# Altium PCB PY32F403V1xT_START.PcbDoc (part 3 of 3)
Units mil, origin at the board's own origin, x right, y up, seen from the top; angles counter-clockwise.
Board outline 1968.43 x 4717 mil, 2 copper layers (Top Layer, Bottom Layer), stack 21 mil thick; 170 components, 200 nets, 718 pads, 400 vias.
Unrouted connection lines stored in the file: 1.

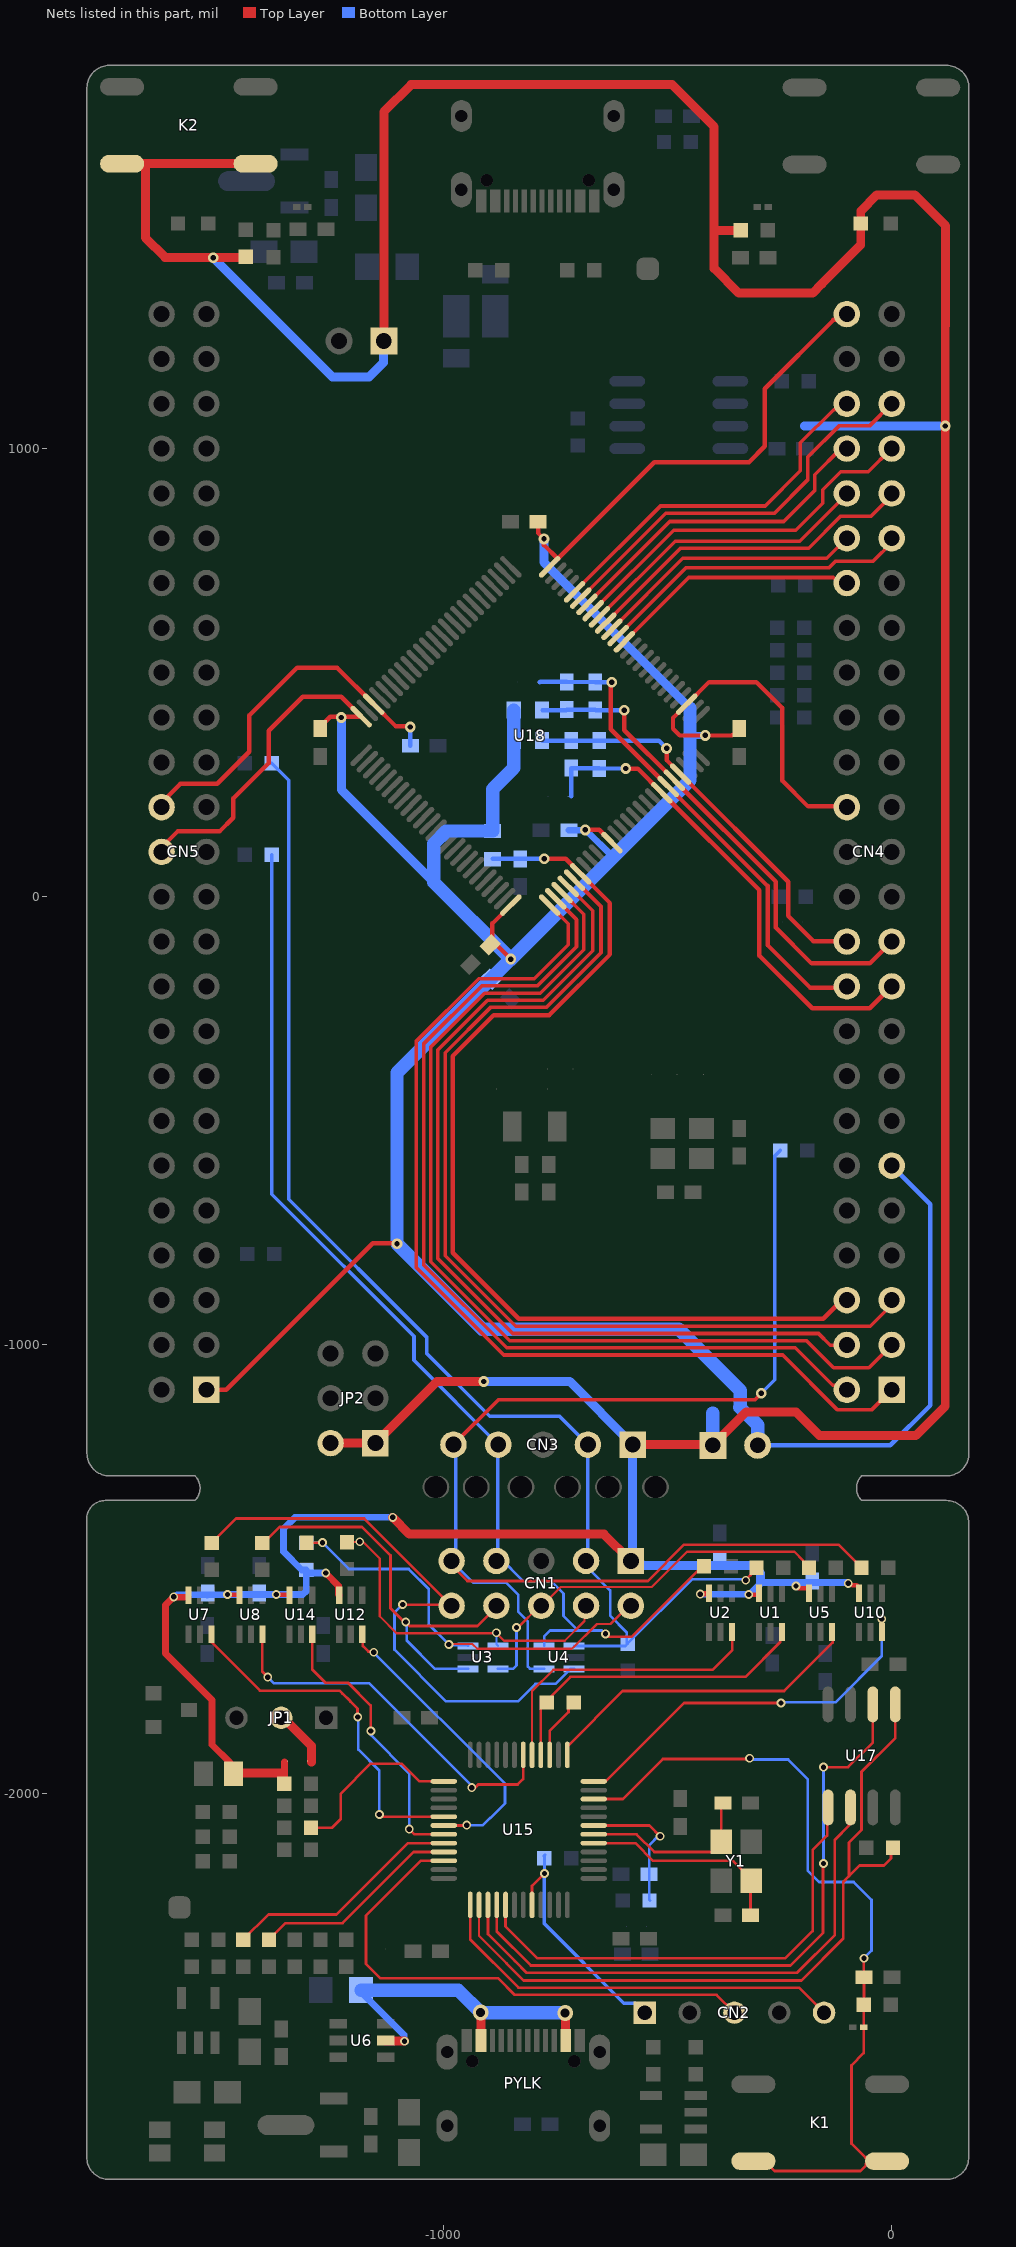
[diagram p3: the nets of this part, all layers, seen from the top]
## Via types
v1: diameter 24, hole 12, Top Layer to Bottom Layer, tented both sides, 237 vias
v2: diameter 19.68, hole 11.81, Top Layer to Bottom Layer, tented both sides, 106 vias
v3: diameter 19.68, hole 11.81, Top Layer to Bottom Layer, 38 vias
v4: diameter 35, hole 20, Top Layer to Bottom Layer, tented both sides, 11 vias
v5: diameter 40, hole 20, Top Layer to Bottom Layer, tented both sides, 6 vias
v6: diameter 30, hole 15, Top Layer to Bottom Layer, tented both sides, 2 vias

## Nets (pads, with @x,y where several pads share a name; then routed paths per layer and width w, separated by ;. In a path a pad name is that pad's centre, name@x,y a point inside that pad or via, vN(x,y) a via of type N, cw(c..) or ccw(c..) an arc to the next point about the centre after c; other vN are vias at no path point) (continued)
PE2: CN4.1 U18.1 | length 2250.2
  Top Layer w8: U18.1@-763.37,-18.46 -721.75,-60.08 -721.75,-107.37 -797.33,-182.95 -921.6,-182.95 -1060.44,-321.79 -1060.44,-827.94 -865.89,-1022.49 -243.25,-1022.49 -120.73,-1145 -45,-1145 CN4.1@0,-1100
PE3: CN4.2 U18.2 | length 2109.7
  Top Layer w8: U18.2@-749.46,-4.54 -703.17,-50.83 -703.17,-111.42 -790.7,-198.95 -914.97,-198.95 -1044.44,-328.41 -1044.44,-820.92 -858.87,-1006.49 -215.22,-1006.49 -131.47,-1090.23 -109.77,-1090.23 CN4.2@-100,-1100
PE4: CN4.3 U18.3 | length 2205.2
  Top Layer w8: U18.3@-735.54,9.38 -687.17,-38.98 -687.17,-118.04 -784.08,-214.95 -908.35,-214.95 -1028.44,-335.04 -1028.44,-814.29 -852.24,-990.49 -189.92,-990.49 -129.68,-1050.73 -50.73,-1050.73 CN4.3@0,-1000
PE5: CN4.4 U18.4 | length 2067.1
  Top Layer w8: U18.4@-721.62,23.3 -667.26,-31.07 -667.26,-120.76 -777.45,-230.95 -901.72,-230.95 -1012.44,-341.67 -1012.44,-807.66 -845.61,-974.49 -163.21,-974.49 -136.84,-1000.85 -112.98,-1000.85 -106.92,-1006.92 CN4.4@-100,-1000
PE6: CN4.5 U18.5 | length 2171.5
  Top Layer w8: U18.5@-707.7,37.22 -648.68,-21.8 -648.68,-124.81 -770.82,-246.95 -895.09,-246.95 -996.44,-348.3 -996.44,-801.03 -838.99,-958.49 -181.02,-958.49 ; -181,-958.47 -48.15,-958.47 0,-910.32 CN4.5@0,-900
PE7: CN4.38 U18.38 | length 560.9
  Top Layer w8: U18.38@-596.34,568.94 -452.84,712.44 -130.21,712.44 -127.55,709.77 -109.77,709.77 CN4.38@-100,700
PE8: CN4.39 U18.39 | length 706
  Top Layer w8: U18.39@-610.27,582.86 -459.39,733.73 -140.26,733.73 -124.98,749.02 -41.05,749.02 0,790.07 CN4.39@0,800
PE9: CN4.40 U18.40 | length 608.4
  Top Layer w8: U18.40@-624.18,596.78 -465.84,755.12 -144.88,755.12 CN4.40@-100,800
PE10: CN4.41 U18.41 | length 760.7
  Top Layer w8: U18.41@-638.1,610.7 -471.4,777.4 -185.4,777.4 -113.36,849.44 -45.76,849.44 0,895.2 CN4.41@0,900
PE11: CN4.42 U18.42 | length 667.1
  Top Layer w8: U18.42@-652.02,624.62 -483.23,793.4 -204.85,793.4 -100,898.25 CN4.42@-100,900
PE12: CN4.43 U18.43 | length 833.4
  Top Layer w8: U18.43@-665.94,638.54 -486.6,817.88 -214.28,817.88 -154.17,878 -154.17,908.32 -113.99,948.5 -52.05,948.5 -0.55,1000 CN4.43@0,1000
PE13: CN4.44 U18.44 | length 744.3
  Top Layer w8: U18.44@-679.86,652.45 -495.04,837.28 -240.81,837.28 -171.71,906.37 -171.71,941.4 -113.11,1000 CN4.44@-100,1000
PE14: CN4.45 U18.45 | length 902.7
  Top Layer w8: U18.45@-693.78,666.38 -504.2,855.96 -261.48,855.96 -187.71,929.73 -187.71,980.43 -117.59,1050.55 -49.49,1050.55 CN4.45@-0.3,1099.74
PE15: CN4.46 U18.46 | length 817.9
  Top Layer w8: U18.46@-707.7,680.29 -516.03,871.96 -282.46,871.96 -203.71,950.71 -203.71,1012.82 -129.63,1086.9 -126.92,1086.9 -113.82,1100 CN4.46@-100,1100
PYLK_BOOT0: CN2.1 R28.1 U15.44 | length 531.3
  Top Layer w6: U15.44@-802.47,-2249.32 -802.47,-2206.93 v2(-774.79,-2179.25)
  Bottom Layer w6: v2(-774.79,-2179.25) -774.79,-2142.1 -776.51,-2140.37 R28.1@-773.74,-2137.6
  Bottom Layer w8: v2(-774.79,-2179.25) -774.79,-2291.51 -597.6,-2468.7 -571.9,-2468.7 -564,-2476.6 CN2.1@-564,-2483.1
PYLK_KEY: C6.2 K1.1 K1.2 R16.1 U11.1 U15.10 | length 1855
  Top Layer w6: U15.10@-664.68,-2013.1 -599.86,-2013.1 -510.56,-1923.8 -318.8,-1923.8 v2(-317,-1922) ; K1.2@-320.45,-2813 -291.75,-2813 -261.5,-2843.25 -69.64,-2843.25 -57.98,-2831.59 -57.98,-2827.49 K1.1@-43.49,-2813 ; v2(-62,-2368.3) -62,-2410.6 C6.2@-61.8,-2410.8 -61.8,-2471.8 R16.1@-62,-2472 -62.4,-2472.4 U11.1@-62.4,-2522.3 -62.4,-2580 -89.7,-2607.3 -89.7,-2782 -58.7,-2813 K1.1@-43.49,-2813 ; K1.1@-22.45,-2813 K1.1@-43.49,-2813
  Bottom Layer w6: v2(-317,-1922) -313.94,-1925.06 -304.38,-1925.06 -304.31,-1925.12 -231.08,-1925.12 -187,-1969.2 -187,-2173.24 -162.1,-2198.14 -84.96,-2198.14 -45,-2238.1 -45,-2351.3 v2(-62,-2368.3)
PYLK_NRST: C24.2 R36.1 U15.7 | length 314.8
  Top Layer w6: U15.7@-664.68,-2072.16 -540.64,-2072.16 v2(-516.6,-2096.2)
  Bottom Layer w6: R36.1@-539.3,-2239.6 -540.88,-2238.02 -540.88,-2181.2 -540.88,-2116 -521.08,-2096.2 v2(-516.6,-2096.2)
PYLK_OSCIN: C19.2 U15.5 Y1.3 | length 465.6
  Top Layer w6: U15.5@-664.68,-2111.53 -571.95,-2111.53 -532.58,-2150.9 -353.89,-2150.9 -313.41,-2191.37 Y1.3@-313.41,-2195.31 -314.88,-2196.78 C19.2@-314.88,-2272
PYLK_OSCOUT: C25.2 U15.6 Y1.1 | length 399.8
  Top Layer w6: U15.6@-664.68,-2091.84 -569.01,-2091.84 -529.64,-2131.21 -399.97,-2131.21 -380.34,-2111.59 Y1.1@-380.34,-2108.69 -380.34,-2025.46 C25.2@-376.88,-2022
PYLK_SPI_CS: R35.1 U15.38 U17.1 | length 1667.6
  Top Layer w5: U15.38@-920.58,-2249.32 -920.58,-2318.38 -859.34,-2379.62
  Top Layer w6: -859.34,-2379.62 -821.05,-2417.91 -201.49,-2417.91 -108.12,-2324.53 -108.12,-2198.12 -95.23,-2185.23 ; R35.1@3,-2122 -1.38,-2126.38 -1.38,-2145.31 -17.64,-2161.58 -71.58,-2161.58 -95.23,-2185.23 ; U17.1@8,-1802 8,-1877 -67.31,-1952.31 -67.31,-2081.99 -95.23,-2109.91 -95.23,-2185.23
PYLK_SPI_MISO: U15.40 U17.2 | length 1437.2
  Top Layer w6: U15.40@-881.21,-2249.32 -881.21,-2308.7 -805.2,-2384.7 -226,-2384.7 -153.1,-2311.8 -153.1,-2158.1 v2(-152,-2157) ; v2(-152,-1942) -97,-1942 -42,-1887 U17.2@-42,-1802
  Bottom Layer w6: v2(-152,-2157) v2(-152,-1942)
PYLK_SPI_MOSI: U15.41 U17.5 | length 1077.9
  Top Layer w6: U15.41@-861.53,-2249.32 -861.53,-2297.51 -790.34,-2368.7 -237.58,-2368.7 -176.47,-2307.59 -176.47,-2126.91 -143.87,-2094.31 -143.87,-2033.87 U17.5@-142,-2032
PYLK_SPI_SCK: U15.39 U17.6 | length 1208.9
  Top Layer w6: U15.39@-900.9,-2249.32 -900.9,-2314.64 -840.68,-2374.86 -814.83,-2400.7 -210.93,-2400.7 -126.79,-2316.56 -126.79,-2103.94 -95.06,-2072.21 -95.06,-2035.06 U17.6@-92,-2032
SWD_SCK: CN2.5 U15.37 | length 934
  Top Layer w6: U15.37@-940.27,-2249.32 -940.27,-2326.25 -832.52,-2434 -330,-2434 -206.6,-2434 CN2.5@-150.9,-2489.7
SWD_SDA: CN2.3 U15.34 | length 1199.5
  Top Layer w6: U15.34@-999.32,-2150.9 -1050.89,-2150.9 -1172.95,-2272.96 -1172.95,-2381.29 -1141.43,-2412.8 -878.25,-2412.8 -841.05,-2450 -514,-2450 -390.6,-2450 CN2.3@-350.9,-2489.7
T_RESET: CN1.9 CN3.5 R18.2 R40.1 U4.4 | length 2919.2
  Top Layer w6: CN1.9@-974.22,-1499.22 -946.8,-1526.64 -544.09,-1526.64 -463.01,-1445.56 -118.94,-1445.56 R18.2@-67.51,-1497
  Top Layer w8: CN3.5@-977.74,-1222.44 -976.49,-1221.18 -877.3,-1122 -305,-1122 v1(-291,-1108)
  Bottom Layer w6: CN1.9@-982,-1482 -933.78,-1530.22 -860.98,-1530.22 -832.9,-1558.31 -832.9,-1595.58 -811.85,-1616.63 -811.85,-1717.69 -807.39,-1722.15 -775.91,-1722.15 U4.4@-775.46,-1722.59
  Bottom Layer w8: CN1.9@-982,-1482 -972.96,-1472.96 -972.96,-1227.22 CN3.5@-977.74,-1222.44 ; v1(-291,-1108) -260.91,-1077.91 -260.91,-582.69 -260.55,-582.33 -260.55,-578 R40.1@-248.55,-566
T_RESETa: U10.3 U15.12 | length 870.1
  Top Layer w6: U15.12@-664.68,-1973.73 -638.21,-1973.73 -463.53,-1799.04 -375.47,-1799.04 v2(-247.09,-1799.04) ; v2(-22.18,-1611.3) -21.92,-1611.56 U10.3@-21.92,-1640.31
  Bottom Layer w6: v2(-247.09,-1799.04) -245.35,-1797.3 -125.6,-1797.3 -22.18,-1693.89 v2(-22.18,-1611.3)
T_RTCK_DTRa: U5.3 U15.13 | length 731.2
  Top Layer w6: U15.13@-723.73,-1914.68 -723.73,-1895.43 -600.3,-1772 -240.01,-1772 -131.82,-1663.81 -131.82,-1641.84 U5.3@-133.34,-1640.31
T_RTCK_VCP_DTR: CN1.6 R10.2 U3.5 | length 868.3
  Top Layer w5: v2(-837.19,-1630.33) -833.76,-1630.33 -785.43,-1582 CN1.6@-782,-1582 -780.37,-1582 -738.51,-1540.14 -535.27,-1540.14 -456.7,-1461.56 -217.02,-1461.56 -196.65,-1481.93 -196.65,-1485 R10.2@-184.65,-1497
  Bottom Layer w6: U3.5@-878.54,-1722.59 -844.49,-1722.59 -837.19,-1715.29 v2(-837.19,-1630.33)
T_TCK_SWCLK: CN1.7 CN3.4 R7.2 R39.1 U4.5 | length 2512.5
  Top Layer w6: CN1.7@-877,-1472 CN1.7@-875.65,-1470.65 ; v2(-638.5,-1644.68) -631.86,-1651.31 -580.04,-1651.31 -425.72,-1497 R7.2@-418.94,-1497
  Bottom Layer w6: CN1.7@-874.5,-1474.5 -821.53,-1527.47 -759.35,-1527.47 -732.4,-1554.43 -732.4,-1604.46 -699.86,-1637 ; U4.5@-775.46,-1671.41 -775.46,-1650.46 -762,-1637 -699.86,-1637 ; v2(-638.5,-1644.68) -646.18,-1637 -699.86,-1637
  Bottom Layer w8: R39.1@-1383.09,94 -1383.09,-663.41 -1065.8,-980.7 -1065.8,-1034.38 CN3.4@-877.74,-1222.44 ; CN1.7@-882,-1482 -879.21,-1479.21 CN3.4@-879.21,-1222.44
T_TCK_SWCLKa: U2.3 U15.17 | length 668.1
  Top Layer w5: U15.17@-802.47,-1914.68 -802.47,-1772.24 -755.23,-1725
  Top Layer w6: -755.23,-1725 -649.38,-1725 -399.57,-1725 -355.59,-1681.02 -355.59,-1640.92 U2.3@-356.2,-1640.31
T_TDI_VCP_TX: CN1.4 R22.2 U3.4 | length 783.1
  Top Layer w5: R22.2@-1215.37,-1439.89 -1179.1,-1439.89 -1142.46,-1476.52 -1142.46,-1605.38 -1104.71,-1643.14 v2@-882,-1643.14 ; R22.2@-1215.37,-1436.89 R22.2@-1213.87,-1438.39 ; v2@-881.98,-1643.14 -865.22,-1659.89 -729.24,-1659.89 -685.44,-1616.1 -685.44,-1585.44 CN1.4@-682,-1582
  Bottom Layer w5: v2@-881.94,-1642.06 -881.94,-1668 U3.4@-878.54,-1671.41
  other v2: -882,-1642
  other v3: -1187.04,-1439.02
T_TDI_VCP_TXa: U12.3 U15.30 | length 672.4
  Top Layer w6: U12.3@-1181.29,-1645.31 -1180.07,-1646.53 -1180.07,-1671.63 -1167.76,-1683.94 -1157.44,-1683.94 v2(-1155.69,-1685.69) ; U15.30@-999.32,-2072.16 -948.98,-2072.16 v2(-948.24,-2071.42)
  Bottom Layer w6: v2(-1155.69,-1685.69) -862.91,-1978.47 -862.91,-2023.08 -895.44,-2055.62 -896.29,-2055.62 -912.09,-2071.42 v2(-948.24,-2071.42)
T_TDO_SWO: CN1.10 R13.2 U4.3 | length 1333.3
  Top Layer w6: R13.2@-1517.34,-1441.92 -1462.53,-1387.1 -1176.9,-1387.1 CN1.10@-988.49,-1575.51 ; v2(-1091.13,-1579.25) -1090.46,-1579.92 -992.9,-1579.92 CN1.10@-988.49,-1575.51 ; CN1.10@-982,-1582 CN1.10@-988.49,-1575.51
  Bottom Layer w6: v2(-1091.13,-1579.25) -1109.17,-1597.28 -1109.17,-1679.92 -993.94,-1795.14 -833.71,-1795.14 -794.58,-1756.01 -750.55,-1756.01 -717.12,-1722.59 U4.3@-708.54,-1722.59 U4.3@-710.85,-1724.9
T_TDO_SWOa: U7.3 U15.29 | length 807.7
  Top Layer w6: U7.3@-1517.86,-1645.31 -1517.86,-1663.14 -1409.54,-1771.46 -1231.92,-1771.46 -1225.37,-1778 -1224.99,-1778 -1208,-1794.99 -1208,-1795.37 -1192.07,-1811.3 -1192.07,-1829.31 v2(-1191.38,-1830) ; v2(-1143.12,-2047.67) -1138.32,-2052.47 -1055.45,-2052.47 U15.29@-999.32,-2052.47
  Bottom Layer w6: v2(-1191.38,-1830) -1190.05,-1831.32 -1190.05,-1903.07 -1143.12,-1950 v2(-1143.12,-2047.67)
T_TMS_SWDIO: CN1.3 CN3.2 R2.2 R5.2 R37.1 U4.1 | length 2854.9
  Top Layer w6: CN1.3@-677.63,-1495.81 CN1.3@-671.44,-1502 ; v2@-325.38,-1523.69 -314.79,-1513.1 -314.79,-1510 R2.2@-301.79,-1497
  Bottom Layer w6: U4.1@-708.23,-1671.71 -594.21,-1671.71 R5.2@-589.1,-1666.6 ; CN1.3@-673.41,-1502.3 -628.14,-1547.58 -628.14,-1604.11 -591.19,-1641.06 -591.19,-1664.51 R5.2@-589.1,-1666.6 ; v2(-325.57,-1524.93) -327.75,-1522.75 -445.25,-1522.75 R5.2@-589.1,-1666.6
  Bottom Layer w8: R37.1@-1383.09,298 -1345,259.91 -1345,-675.04 -1037.8,-982.24 -1037.8,-1018.2 -896.91,-1159.09 -741.09,-1159.09 CN3.2@-677.74,-1222.44 -678,-1222.7 -678,-1478 CN1.3@-682,-1482
T_TMS_SWDIOa: R32.1 U1.3 U15.16 | length 723.8
  Top Layer w6: U15.16@-782.79,-1914.68 R32.1@-782.79,-1794.63 ; R32.1@-769.54,-1797.63 -769.54,-1793.01 -716.88,-1740.35 -660.3,-1740.35 -325.78,-1740.35 -248.66,-1663.23 -248.66,-1644.2 U1.3@-244.77,-1640.31
T_TMS_SWDIOa_OUT: R32.2 U15.15 | length 143.2
  Top Layer w6: U15.15@-763.1,-1914.68 -763.1,-1861.36 -721.18,-1819.44 R32.2@-721.18,-1788.84
T_TRST_RTSa: U8.3 U15.18 | length 840.3
  Top Layer w6: U8.3@-1404.14,-1645.31 -1404.14,-1729.14 v2(-1392.18,-1741.1) ; v2(-937.08,-1987.65) -933.17,-1991.56 -922.46,-1980.84 -834.61,-1980.84 -822.16,-1968.4 U15.18@-822.16,-1914.68
  Bottom Layer w6: v2(-1392.18,-1741.1) -1378.19,-1755.09 -1165.35,-1755.09 -937.08,-1983.36 v2(-937.08,-1987.65)
T_TRST_VCP_RTS: CN1.8 R14.2 U3.1 | length 935
  Top Layer w6: R14.2@-1404.7,-1441.9 -1401.46,-1441.9 -1365.76,-1406.2 -1181.75,-1406.2 -1118.42,-1469.53 -1118.42,-1587.44 -1087.6,-1618.27 v2(-1084.14,-1618.27) -1075.4,-1627 -924.33,-1627 -877,-1579.67 CN1.8@-877,-1572
  Bottom Layer w6: v2(-1084.14,-1618.27) -1082,-1620.4 -1082,-1659.4 -1018.81,-1722.59 U3.1@-945.46,-1722.59
T_VCP_RX: CN1.2 R23.1 R26.2 U3.3 | length 1000.9
  Top Layer w5: v2(-988.03,-1668.26) -986.77,-1667 -935.58,-1667 -924.55,-1678.03 -713.09,-1678.03 -657.7,-1622.64 -627.64,-1622.64 CN1.2@-577,-1572
  Top Layer w6: R26.2@-1305.8,-1441.3 -1270.3,-1441.3 v3(-1270,-1441) ; R26.2@-1305.8,-1430.15 R26.2@-1305.68,-1430.03
  Bottom Layer w6: R23.1@-1306,-1442 -1305,-1441 v3(-1270,-1441) -1211.28,-1499.72 -1077.74,-1499.72 -1032.95,-1544.5 -1032.95,-1623.34 v2(-988.03,-1668.26) -988.77,-1669 -988.77,-1670.23 -946.64,-1670.23 U3.3@-945.46,-1671.41
T_VCP_RXa: U14.3 U15.31 | length 636
  Top Layer w6: U14.3@-1292.72,-1645.31 -1292.72,-1724.71 -1263.73,-1753.7 -1213.46,-1753.7 -1162.6,-1804.57 -1162.6,-1860.62 v2(-1162,-1861.22) ; v2(-1076.6,-2080.25) -1065.01,-2091.84 U15.31@-999.32,-2091.84
  Bottom Layer w6: v2(-1162,-1861.22) -1162,-1870.58 -1076.6,-1955.98 v2(-1076.6,-2080.25)
TVDD: C12.2 C13.2 C14.2 C15.2 CN1.1 CN3.1 JP2.1 JP2.2 JP3.1 JP4.1 K2.1 K2.2 LED_PA1.1 R15.2 R17.2 R23.2 R34.2 R46.1 R57.1 R64.1 R65.2 U1.6 U2.6 U5.6 U7.6 U8.6 U10.6 U12.6 U14.6 | length 11583
  Top Layer w6: U8.6@-1455.33,-1558.69 U8.6@-1452.44,-1555.8 ; U14.6@-1343.9,-1558.69 U14.6@-1341.01,-1555.8
  Top Layer w10: v2(-1482,-1557) -1457.02,-1557 U8.6@-1455.33,-1558.69 ; v3@-1372,-1557 -1345.59,-1557 U14.6@-1343.9,-1558.69 ; v3(-319.12,-1556.91) -297.93,-1556.91 -297.84,-1557 -295.95,-1555.11 U1.6@-295.95,-1553.69 ; v2(-213.71,-1537.94) -208.39,-1543.26 -184.53,-1543.26 U5.6@-184.53,-1553.69 ; v2@-88.32,-1535.9 -78.09,-1535.9 -73.1,-1540.9 U10.6@-73.1,-1553.69
  Top Layer w12: v2@-426.1,-1555.1 U2.6@-407.99,-1555.1
  Top Layer w15: v2(-1602,-1562) -1620.34,-1580.34 -1620.34,-1688.4 -1516.47,-1792.27 -1516.47,-1892.05 -1476.48,-1932.04 -1476.48,-1949.05 R15.2@-1468.54,-1957 R15.2@-1466.76,-1955.22 ; v2@-1601.37,-1562.63 U7.6@-1569.65,-1562.63 ; -1358.93,-1955.22 -1354.92,-1959.23 ; R17.2@-1354.92,-1987.98 -1354.92,-1959.23 ; -1354.92,-1930.48 -1354.92,-1959.23 ; v3(-1262.72,-1508.95) -1234.16,-1537.51 -1234.16,-1557 U12.6@-1232.47,-1558.69 ; v2(-427,-1556) v2@-426.1,-1555.1
  Top Layer w20: K2.2@-1715,1636 -1665.16,1636 ; R15.2@-1466.76,-1955.22 -1358.93,-1955.22 ; R65.2@-1441,1428 -1441,1426.65 -1620.9,1426.65 -1665.16,1470.91 -1665.16,1636 ; K2.1@-1417,1636 -1665.16,1636 ; JP2.2@-1252,-1219 JP2.1@-1152,-1219 -1014.4,-1081.4 v1(-910.3,-1081.4) ; JP3.1@-1133,1240 -1133,1751 -1072,1812 -490,1812 -396,1718 -396,1486.7 ; v3(-1113.37,-1384.62) -1076.09,-1421.9 -642.1,-1421.9 CN1.1@-582,-1482 ; CN3.1@-577.74,-1222.44 JP4.1@-399,-1222.44 ; JP4.1@-399,-1224 -324.46,-1149.46 -213.92,-1149.46 -161,-1202.38 53.62,-1202.38 119.5,-1136.5 119.5,1273.7 120.34,1274.54 120.34,1496.66 51,1566 -33,1566 -69,1530 LED_PA1.1@-69,1502 -69,1454.4 -156,1367.4 -176.4,1347 -341,1347 -396,1402 -396,1486.7 ; R57.1@-336.8,1486.9 -337,1486.7 -396,1486.7
  Bottom Layer w15: v2(-1602,-1562) -1598.21,-1562 -1593.33,-1557.12 C15.2@-1528.13,-1557.12 ; C15.2@-1527,-1558.26 C15.2@-1528.13,-1557.12 ; v2@-1482.12,-1557.12 C15.2@-1528.13,-1557.12 ; v2(-1482,-1557) v3(-1373.23,-1557) -1314,-1557 -1306,-1549 R23.2@-1306,-1508.95 ; v3(-1262.72,-1508.95) R23.2@-1306,-1508.95 ; v3(-1113.37,-1384.62) -1331.62,-1384.62 -1357,-1410 -1357,-1461.24 -1316.24,-1502 R23.2@-1306,-1502 R23.2@-1306,-1508.95 ; v2@-426.62,-1556.38 v3@-319.64,-1556.38 ; v3(-319.12,-1556.91) -317.85,-1556.91 -315.51,-1554.57 -314.91,-1554.57 -290.42,-1530.08 ; -292.28,-1530.08 -290.42,-1530.08 ; v2(-97,-1532) -98.92,-1530.08 -290.42,-1530.08
  Bottom Layer w20: v1@-1514,1425.79 -1247.61,1159.4 -1166.6,1159.4 -1134.28,1191.72 -1134.28,1238.72 JP3.1@-1133,1240 ; v1(-910.3,-1081.4) -718.78,-1081.4 CN3.1@-577.74,-1222.44 JP4.1@-399,-1222.44 ; CN1.1@-578.06,-1478.06 CN3.1@-578.06,-1222.76 ; CN1.1@-574.96,-1473.74 -553.54,-1492 -310.1,-1492 -292.28,-1509.82 -292.28,-1530.08 ; -195,1050 119,1050 v1(119.5,1050.5)
  Bottom Layer w30: JP4.1@-399,-1224 -399,-1222.44 -399,-1166 -398.9,-1165.9 -398.9,-1151.8
  other v1: -1514,1426
TVDD*: JP1.2 R34.1 | length 129
  Top Layer w20: JP1.2@-1362,-1832 -1357.27,-1832 -1294.92,-1894.35 -1294.92,-1930.48
TVDD_DISCHARGE_EN: R19.2 U15.25 | length 404.9
  Top Layer w6: R19.2@-1295.47,-2077.22 -1248.49,-2077.22 -1229.52,-2058.25 -1229.52,-2001.45 -1162.42,-1934.34 -1093.39,-1934.34 -1054,-1973.73 U15.25@-999.32,-1973.73
USB_DM: R11.2 U15.32 | length 536.9
  Top Layer w6: R11.2@-1447,-2327 -1390.6,-2270.6 -1238.72,-2270.6 -1079.64,-2111.53 U15.32@-999.32,-2111.53
USB_DP: R12.2 U15.33 | length 471.3
  Top Layer w6: R12.2@-1389.5,-2327 -1352.55,-2290.05 -1225.27,-2290.05 -1066.44,-2131.21 U15.33@-999.32,-2131.21
VBAT: C28.2 CN4.6 L1.1 U18.6 | length 2258.5
  Top Layer w10: v1(-775.39,84.69) -727.33,84.69 -628.55,-14.09 -628.55,-128.73 -763.78,-263.95 -888.05,-263.95 -979.44,-355.34 -979.44,-793.99 -831.94,-941.49 -188.06,-941.49 ; -188.05,-941.47 -153.05,-941.47 -111.58,-900 CN4.6@-100,-900
  Bottom Layer w10: L1.1@-890.4,84.69 v1(-775.39,84.69)
VBUS_PYLK: F1.1 PYLK.A4 PYLK.A9 PYLK.B4 PYLK.B9 U6.5 | length 782.3
  Top Layer w10: PYLK.A4@-922.19,-2552.11 PYLK.B9@-910.38,-2552.11 ; PYLK.B4@-733.22,-2552.12 PYLK.A9@-721.4,-2552.12
  Top Layer w20: U6.5@-1128.85,-2552 -1128.02,-2552.83 -1087.42,-2552.83 v2(-1086.8,-2553.45) ; PYLK.A4@-916.58,-2534.77 v4@-916.58,-2489.92 ; v4(-728.6,-2490.7) -727.63,-2491.67 PYLK.B4@-727.63,-2532.29
  Bottom Layer w15: F1.1@-1186.06,-2441.24 -1087.69,-2539.61 -1087.69,-2552.55 v2(-1086.8,-2553.45)
  Bottom Layer w30: F1.1@-1184.02,-2439.7 -966.8,-2439.7 v4(-917,-2489.5) ; v4@-916.51,-2489.99 -916.4,-2490.1 -729.2,-2490.1 v4(-728.6,-2490.7)
VCAP: C34.1 CN5.28 U18.73 | length 837.9
  Top Layer w10: CN5.28@-1639,200 -1586.89,252.11 -1505.01,252.11 -1433.52,323.61 -1433.52,404.57 -1326.79,511.3 -1237.45,511.3 U18.73@-1155.9,429.74 -1106.1,379.95 -1075.15,379.95 v1(-1074.1,378.9)
  Bottom Layer w10: C34.1@-1074.1,337.1 v1(-1074.1,378.9)
VCCA: C37.2 C38.2 CN4.22 L2.2 U18.22 | length 924.4
  Top Layer w10: v1(-502.3,331) -502.3,305.09 U18.22@-471.06,273.86 -231,33.79 -231,-42.75 -174.95,-98.8 -101.2,-98.8 CN4.22@-100,-100
  Bottom Layer w10: L2.2@-779.1,348.3 C37.2@-715.7,348.3 ; C37.2@-715.2,348.6 C38.2@-652.6,348.6 -519.9,348.6 v1(-502.3,331)
VDD: C26.2 C29.2 C31.1 C33.1 C41.2 C42.2 CN4.11 CN4.28 CN4.50 CN5.1 CN5.26 JP4.2 L1.2 L2.1 L3.1 R64.2 U18.11 U18.28 U18.50 U18.75 U18.100 | length 8863.1
  Top Layer w10: CN5.26@-1639,100 -1593.35,145.65 -1499.72,145.65 -1468.95,176.42 -1468.95,219.44 -1389.98,298.41 -1389.98,370.25 -1313.87,446.36 -1228.19,446.36 U18.75@-1183.74,401.91 -1252.43,401.9 -1265,389.33 -1265,385 C31.1@-1275,375 ; CN5.1@-1539,-1100 CN5.1@-1529,-1100 -1484.6,-1100 -1157.7,-773.1 v1@-1104.1,-773.1 ; v1(-850,-139) -890.8,-98.2 -890.8,-59.59 U18.100@-849.67,-18.46 ; C41.2@-789,837 -789,811.63 v1(-775.9,798.53) -775.9,784.68 U18.50@-745.28,754.07 ; U18.50@-763.37,735.97 U18.50@-745.28,754.07 ; v1(-683.6,149.2) -652.64,149.2 U18.11@-624.18,120.74 ; U18.28@-457.15,429.74 -487.95,398.95 -487.95,375.04 -472.74,359.83 -355.86,359.83 -354.68,361 -350,361 -340,371 C33.1@-340,375 ; U18.28@-456.76,429.74 -407.51,479 -302,479 -244.3,421.3 -244.3,259.32 -186.55,201.57 -101.57,201.57 CN4.28@-100,200 ; CN4.50@-100,1300 -113.27,1300 -126.3,1286.97 -129.95,1286.97 -283.12,1133.8 -283.12,1005.05 -318.39,969.79 -529.56,969.79 U18.50@-745.28,754.07
  Bottom Layer w10: -450,359 -449,360 ; JP4.2@-299,-1224 -3,-1224 86,-1135 86,-686 CN4.11@0,-600
  Bottom Layer w15: C29.2@-720.1,148.2 -719.6,148.7 -684.1,148.7 v1(-683.6,149.2) -682.61,149.2 -621.7,88.3 ; -449,360 v1(-416,360)
  Bottom Layer w20: v1(-1228,400) -1228,239 -1021.75,32.75 ; v1(-850,-139) v1@-849,-139 ; v1(-775.9,798.53) -775.9,746.9 -450,421
  Bottom Layer w30: v1@-849,-139 -621.7,88.3 -450,260 -450,359 -450,421 ; L3.1@-843.3,416.6 -843.3,287.45 -890.4,240.34 L1.2@-890.4,146.7 -993.4,146.7 -1021.75,118.35 -1021.75,32.75 v1(-850,-139) -894.5,-183.5 -1103.7,-392.7 v1(-1103.7,-774.2) -913.4,-964.5 -475.27,-964.5 -337.5,-1102.27 -337.5,-1137.3 -338.91,-1138.71 ; -335.54,-1142.09 -299,-1178.62 JP4.2@-299,-1224 ; CN4.50@-104.53,1295.47 CN4.50@-100,1300
VREF+: C39.2 C40.2 CN4.21 L3.2 U18.21 | length 1120
  Top Layer w10: v1(-596.6,415.9) -596.6,371.55 -485.9,260.85 U18.21@-484.99,260.85 ; U18.21@-484.99,259.93 -259.03,33.98 -259.03,-68.57 -178.78,-148.81 -48.81,-148.81 CN4.21@0,-100
  Bottom Layer w10: L3.2@-779.1,416.6 -725.9,416.6 C39.2@-724.9,417.6 -662,417.6 C40.2@-661.6,417.2 -660.3,415.9 v1(-596.6,415.9)
VREF-: C39.1 C40.1 CN4.20 R56.2 U18.20 | length 1111.6
  Top Layer w10: v1(-624.5,478.9) -626.5,476.9 -626.5,373.61 -499.44,246.55 U18.20@-498.9,246.55 ; U18.20@-498.9,246.02 -277.03,24.14 -277.03,-107.67 -181.3,-203.4 -103.4,-203.4 CN4.20@-100,-200
  Bottom Layer w10: -785.37,478.73 -784.5,479.6 C39.1@-724.9,479.6 -724.5,479.6 -724.1,479.2 C40.1@-661.6,479.2 -661.3,478.9 v1(-624.5,478.9)
VSSA: C37.1 C38.1 CN4.19 R51.2 U18.19 | length 1105.5
  Top Layer w10: v1(-593.2,286.2) -592.47,285.47 -566.2,285.47 U18.19@-512.83,232.09 -295.03,14.3 -295.03,-131.49 -177.51,-249.01 -49.01,-249.01 CN4.19@0,-200
  Bottom Layer w10: -715.3,224.1 -715.3,286.7 -715.21,286.6 C38.1@-652.6,286.6 -652.2,286.2 v1(-593.2,286.2)
pads on no net: PYLK. PYLK.A8 PYLK.B8 U15.42 U15.45 USB. USB.A8 USB.B8

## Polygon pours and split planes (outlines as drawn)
GND on Bottom Layer "NONET_L-01_P-001" (solid, remove dead copper, pour order 3): -1795.3,1862.4 174.86,1862.4 174.86,-2863.5 -1805.69,-2863.5
GND on Top Layer "NONET_L-01_P-001" (solid, remove dead copper, pour order 4): -1788.5,1862.4 183.89,1862.4 183.89,-2864.2 -1798.89,-2864.2

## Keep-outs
Keep-Out Layer:
  lines w8: -1796,-2812 ccw(c-1746,-2812) -1746,-2862 -1618.26,-2862 -4.09,-2862 122,-2862 ccw(c122,-2812) 172,-2812 172,-1397 ccw(c122,-1397) 122,-1347 33,-1347 -67,-1347 cw(c-39.5,-1319.5) -67,-1292 33,-1292 122.43,-1292 ccw(c122.43,-1242) 172.43,-1242 172.43,1805 ccw(c122.43,1805) 122.43,1855 24.65,1855 -4.09,1855 -1618.26,1855 -1647,1855 -1745.43,1855 ccw(c-1745.43,1805) -1795.43,1805 -1795.43,-1242 ccw(c-1745.43,-1242) -1745.43,-1292 -1696,-1292 -1654.5,-1292 -1554.5,-1292 cw(c-1582,-1319.5) -1554.5,-1347 -1654.5,-1347 -1755,-1347 ccw(c-1755,-1388) -1796,-1388 -1796,-2812 ; -1482,-1347 cw(c-1454.5,-1319.5) -1482,-1292 -1132,-1292 -1112,-1292 cw(c-1139.5,-1319.5) -1112,-1347 -1132,-1347 -1482,-1347 ; -437,-1347 cw(c-409.5,-1319.5) -437,-1292 -417,-1292 -137,-1292 cw(c-164.5,-1319.5) -137,-1347 -417,-1347 -437,-1347

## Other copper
Top Layer:
  pour cut-out: -42,-1492 -32,-1492 -32,-1502 -42,-1502
  pour cut-out: -1422,-2372 -1412,-2372 -1412,-2382 -1422,-2382
  pour cut-out: -1422,-2337 -1412,-2337 -1412,-2347 -1422,-2347
  pour cut-out: -1367,-2337 -1361.5,-2337 -1361.5,-2359 -1367,-2359
  pour cut-out: -1367,-2372 -1357,-2372 -1357,-2382 -1367,-2382
  region net 5V_USB_CHGR: -1312,-2627 -1302,-2617 -1277,-2617 -1232,-2662 -1187,-2662 -1167,-2682 -1037,-2682 -1037,-2742 -1182,-2742 -1182,-2722 -1207,-2697 -1262,-2697 -1297,-2662 -1312,-2647
  region net 3V3_PYLK: -1458.7,-2546.2 -1408.7,-2546.2 -1388.7,-2566.2 -1343.7,-2566.2 -1338.7,-2571.2 -1338.7,-2611.2 -1353.7,-2626.2 -1353.7,-2696.2 -1336.2,-2713.7 -1343.7,-2721.2 -1405.31,-2721.2 -1405.31,-2707.71 -1393.7,-2696.1 -1393.7,-2631.2 -1418.7,-2606.2 -1458.7,-2606.2
  region net 3V3_PYLK: -602,-2707 -592,-2697 -572,-2697 -562,-2707 -562,-2732 -557,-2737 -512,-2737 -507,-2742 -507,-2757 -512,-2762 -567,-2762 -602,-2727
  region net 3V3_USB_PYLK: -469.5,-2742 -397,-2742 -382,-2727 -362,-2727 -352,-2737 -352,-2757 -367,-2772 -382,-2772 -407,-2797 -407,-2837 -472,-2837 -472,-2743.67
  pour cut-out: -1307,-2367 -1297,-2367 -1297,-2377 -1307,-2377
  pour cut-out: -1252,-2367 -1242,-2367 -1242,-2377 -1252,-2377
  pour cut-out: -69.57,-1825 -59.57,-1825 -59.57,-1835 -69.57,-1835
  pour cut-out: -22,-1787 -12,-1787 -12,-1797 -22,-1797
Bottom Layer:
  pour cut-out: -798,482 -777,482 -777,332 -775,330 -778,327 -799,327 -799,479 -798,480

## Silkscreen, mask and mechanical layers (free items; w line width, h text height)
Top Overlay:
  drawing of 1057 lines, arcs and shapes, not listed
  text "NRST" at -102,1550.64 h60
  text "USER_PA0" at -1706,1549.66 h60
  text "50" at -112,1362.54 h50
  text "49" at -11,1362.54 h50
  text "52" at -1550,1358.54 h50
  text "51" at -1649,1357.54 h50
  text "VDD*_SEL" at -1292,1300.89 h50
  text "B13" at -1466,1289.63 h50
  text "B12" at -1777,1286.9 h50
  text "GND" at 55,1285.63 h50
  text "VDD" at -262,1285.09 h50
  text "B15" at -1466,1190.45 h50
  text "B14" at -1777,1187.71 h50
  text "B10" at 68.8,1185.57 h50
  text "B11" at -262,1184 h50
  text "3V3" at -1274,1155.54 h50
  text "VDD*" at -1181,1156 h50
  text "D9" at -1466,1089.66 h50
  text "D8" at -1763.97,1087.46 h50
  text "E15" at -262,1084.54 h50
  text "E14" at 68.8,1085.04 h50
  text "PY32F403-START V2.0" at -992,1006.17 h65
  text "D11" at -1466,988.97 h50
  text "D10" at -1777,987.31 h50
  text "E12" at 68.8,984.51 h50
  text "E13" at -262,983.6 h50
  text "2025-05" at -804.05,935.47 h65
  text "D13" at -1466,890.43 h50
  text "D12" at -1777,887.69 h50
  text "E11" at -262,883.79 h50
  text "E10" at 68.8,883.45 h50
  text "D15" at -1466,789.18 h50
  text "D14" at -1777,786.44 h50
  text "E9" at -262,783.44 h50
  text "E8" at 68.8,782.39 h50
  text "C6" at -1775.9,688.92 h50
  text "C7" at -1466,688.92 h50
  text "B2" at 68.8,685.1 h45
  text "E7" at -262,683.74 h50
  text "C8" at -1775.97,589.74 h50
  text "C9" at -1466,589.74 h50
  text "B0" at 68.8,587.33 h45
  text "B1" at -262,584.04 h50
  text "A8" at -1773.54,488.48 h50
  text "A9" at -1466.04,488.48 h50
  text "C4" at 68.8,485.81 h50
  text "C5" at -262,484.77 h50
  text "A11" at -1466.04,387.23 h50
  text "A10" at -1783.04,386.44 h50
  text "A6" at 68.76,384.74 h50
  text "A7" at -262.04,383.35 h50
  text "A13" at -1466.04,287.51 h50
  text "A12" at -1789.04,286.97 h50
  text "A4" at 68.76,284.32 h50
  text "A5" at -262.04,283.08 h50
  text "VCAP" at -1789,187.2 h45
  text "GND" at -1466,187.25 h50
  text "VDD" at -262,182.2 h50
  text "GND" at 55,181.8 h50
  text "VDD" at -1786.25,87.53 h50
  text "A14" at -1466.04,87.53 h50
  text "A3" at -262.04,83.56 h50
  text "A2" at 59.86,82 h50
  text "C10" at -1466,-12.62 h50
  text "A15" at -1779.54,-16.56 h50
  text "A1" at -262.04,-17 h50
  text "A0" at 59.86,-19.46 h50
  text "C11" at -1780.9,-110.96 h50
  text "C12" at -1466,-111.8 h50
  text "VCCA" at -283,-112.46 h50
  text "VREF+" at 55,-113.75 h40
  text "VSSA" at 55,-211.94 h45
  text "D0" at -1775.79,-213.06 h50
  text "D1" at -1466,-213.59 h50
  text "VREF-" at -295,-218 h50
  text "C2" at 65.3,-311.96 h50
  text "D2" at -1775.58,-314.31 h50
  text "D3" at -1466,-313.78 h50
  text "C3" at -262,-317.64 h50
  text "C0" at 65.3,-413.49 h50
  text "D5" at -1466,-414.03 h50
  text "D4" at -1775.76,-414.57 h50
  text "C1" at -262,-418.44 h50
  text "F1" at 65.3,-514.02 h50
  text "D6" at -1775.9,-514.75 h50
  text "D7" at -1466,-515.29 h50
  text "F5" at -262,-518.68 h50
  text "F4" at 65.3,-614.44 h50
  text "B3" at -1773.43,-615.47 h50
  text "B4" at -1466,-616.01 h50
  text "F0" at -262,-619.03 h50
  text "B5" at -1773.68,-715.73 h50
  text "B6" at -1466,-715.73 h50
  text "C15" at 65.3,-715.96 h50
  text "F3" at -262,-719.37 h50
  text "B7" at -1773.43,-816.41 h50
  text "BOOT0" at -1466,-815.88 h50
  text "C13" at 65.3,-817.49 h50
  text "C14" at -262,-820.18 h50
  text "BOOT_SEL" at -1297,-910.01 h45
  text "B8" at -1773.51,-914.95 h50
  text "B9" at -1466,-914.95 h50
  text "E6" at 65.3,-918.55 h50
  text "VBAT" at -278,-920.59 h50
  text "GND" at -1323.08,-1013.1 h45 r90
  text "GND" at -1061.58,-1014.5 h45 r90
  text "E0" at -1773.33,-1016.21 h50
  text "E1" at -1466,-1016.74 h50
  text "E4" at 65.3,-1018.97 h50
  text "E5" at -262,-1020.12 h50
  text "GND" at -1789,-1116.46 h50
  text "VDD" at -1466,-1117 h50
  text "E2" at 65.3,-1119.5 h50
  text "E3" at -262,-1120.46 h50
  text "NRST" at -1039,-1152.52 h45
  text "SWC" at -912.62,-1152.52 h45
  text "GND" at -801.46,-1152.52 h45
  text "SWD" at -695.62,-1152.52 h45
  text "VDD*" at -585,-1153 h45
  text "BOOT1" at -1060.18,-1156.4 h45 r90
  text "BOOT0" at -1323.08,-1159.3 h45 r90
  text "VDD*" at -438,-1171 h45
  text "VDD" at -330,-1174 h45
  text "99" at -1651,-1196.46 h50
  text "100" at -1562,-1197.46 h50
  text "2" at -105.04,-1217 h50
  text "1" at 3,-1220 h50
  text "IDD" at -236,-1235 h45
  text "VDD*" at -1323,-1270 h45 r90
  text "VDD*" at -1060,-1270 h45 r90
  text "NRST" at -1027,-1416.57 h40
  text "SWC" at -907,-1416.57 h40
  text "GND" at -800.14,-1416.57 h40
  text "SWD" at -700.69,-1416.57 h40
  text "VDD*" at -607,-1416.54 h40
  text "DTR" at -800.14,-1686.12 h40
  text "TX" at -700.69,-1686.12 h40
  text "RX" at -607,-1686.12 h40
  text "SWO" at -1027,-1686.57 h40
  text "RTS" at -907,-1686.57 h40
  text "VDD_SEL" at -1184,-1782.01 h45
  text "5V" at -1507,-1786.36 h60
  text "3V3" at -1287,-1786.36 h60
  text "VDD*" at -1432,-1787 h60
  text "VDD" at -504.7,-2437.49 h50
  text "BT0" at -601.1,-2437.6 h50
  text "DIO" at -390.5,-2438.06 h50
  text "GND" at -298.9,-2438.06 h50
  text "CLK" at -189.1,-2437.76 h50
  text "PY-LINK V2.0" at -995.7,-2470.03 h65
Bottom Overlay:
Mechanical 1:
  lines w6: -1482,-1347 -1132,-1347 -1112,-1347 ; -1482,-1292 -1132,-1292 -1112,-1292 ; -437,-1347 -417,-1347 -137,-1347 ; -437,-1292 -417,-1292 -137,-1292
  lines w8: -1482,-1347 cw(c-1454.5,-1319.5) -1482,-1292 ; -1112,-1347 ccw(c-1139.5,-1319.5) -1112,-1292 ; -437,-1347 cw(c-409.5,-1319.5) -437,-1292 ; -137,-1347 ccw(c-164.5,-1319.5) -137,-1292

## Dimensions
174.86,-2863.5 to 106,1854 on Mechanical 1
-1618.26,-2862 to -1702,-1357 on Mechanical 1
-1796,-2864 to 171,-2919 on Mechanical 1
